VERSION 5.8 ;
BUSBITCHARS "[]" ;
DIVIDERCHAR "/" ;
UNITS
    DATABASE MICRONS 1000 ;
END UNITS

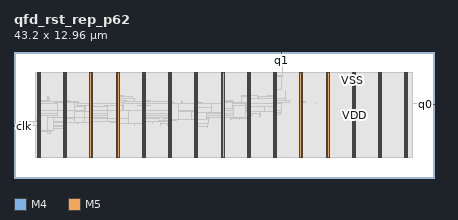
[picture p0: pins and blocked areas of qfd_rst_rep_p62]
MACRO qfd_rst_rep_p62
  FOREIGN qfd_rst_rep_p62 0 0 ;
  CLASS BLOCK ;
  SIZE 43.2 BY 12.96 ;
  PIN clk
    DIRECTION INPUT ;
    USE SIGNAL ;
    PORT
      LAYER M4 ;
        RECT  0 5.328 0.084 5.352 ;
    END
  END clk
  PIN d
    DIRECTION INPUT ;
    USE SIGNAL ;
    PORT
      LAYER M4 ;
        RECT  0 5.424 0.084 5.448 ;
    END
  END d
  PIN q0
    DIRECTION OUTPUT ;
    USE SIGNAL ;
    PORT
      LAYER M4 ;
        RECT  43.116 7.536 43.2 7.56 ;
    END
    PORT
      LAYER M4 ;
        RECT  43.081 7.536 43.164 7.56 ;
    END
  END q0
  PIN q1
    DIRECTION OUTPUT ;
    USE SIGNAL ;
    PORT
      LAYER M5 ;
        RECT  27.504 12.876 27.528 12.96 ;
    END
    PORT
      LAYER M5 ;
        RECT  27.504 12.805 27.528 12.944 ;
    END
  END q1
  PIN VSS
    DIRECTION INOUT ;
    USE GROUND ;
    PORT
      LAYER M5 ;
        RECT  40.2 2.137 40.32 10.823 ;
        RECT  37.5 2.137 37.62 10.823 ;
        RECT  34.8 2.137 34.92 10.823 ;
        RECT  32.1 2.137 32.22 10.823 ;
        RECT  29.4 2.137 29.52 10.823 ;
        RECT  26.7 2.137 26.82 10.823 ;
        RECT  24 2.137 24.12 10.823 ;
        RECT  21.3 2.137 21.42 10.823 ;
        RECT  18.6 2.137 18.72 10.823 ;
        RECT  15.9 2.137 16.02 10.823 ;
        RECT  13.2 2.137 13.32 10.823 ;
        RECT  10.5 2.137 10.62 10.823 ;
        RECT  7.8 2.137 7.92 10.823 ;
        RECT  5.1 2.137 5.22 10.823 ;
        RECT  2.4 2.137 2.52 10.823 ;
    END
  END VSS
  PIN VDD
    DIRECTION INOUT ;
    USE POWER ;
    PORT
      LAYER M5 ;
        RECT  40.392 2.151 40.512 10.809 ;
        RECT  37.692 2.151 37.812 10.809 ;
        RECT  34.992 2.151 35.112 10.809 ;
        RECT  32.292 2.151 32.412 10.809 ;
        RECT  29.592 2.151 29.712 10.809 ;
        RECT  26.892 2.151 27.012 10.809 ;
        RECT  24.192 2.151 24.312 10.809 ;
        RECT  21.492 2.151 21.612 10.809 ;
        RECT  18.792 2.151 18.912 10.809 ;
        RECT  16.092 2.151 16.212 10.809 ;
        RECT  13.392 2.151 13.512 10.809 ;
        RECT  10.692 2.151 10.812 10.809 ;
        RECT  7.992 2.151 8.112 10.809 ;
        RECT  5.292 2.151 5.412 10.809 ;
        RECT  2.592 2.151 2.712 10.809 ;
    END
  END VDD
  # OT_OBS_CLOSED layer=M5 d_um=1.536 added=7
  OBS
    LAYER RVTN ;
     RECT  2.16 2.16 41.04 2.295 ;
     RECT  2.16 2.565 41.04 2.835 ;
     RECT  2.16 3.105 41.04 3.375 ;
     RECT  2.16 3.645 41.04 3.915 ;
     RECT  2.16 4.185 41.04 4.455 ;
     RECT  2.16 4.725 41.04 4.995 ;
     RECT  2.16 5.265 41.04 5.535 ;
     RECT  2.16 5.805 41.04 6.075 ;
     RECT  2.16 6.345 41.04 6.615 ;
     RECT  2.16 6.885 41.04 7.155 ;
     RECT  2.16 7.425 41.04 7.695 ;
     RECT  2.16 7.965 41.04 8.235 ;
     RECT  2.16 8.505 41.04 8.775 ;
     RECT  2.16 9.045 41.04 9.315 ;
     RECT  2.16 9.585 41.04 9.855 ;
     RECT  2.16 10.125 41.04 10.395 ;
     RECT  2.16 10.665 41.04 10.8 ;
    LAYER RVTP ;
     RECT  2.16 2.295 41.04 2.565 ;
     RECT  2.16 2.835 41.04 3.105 ;
     RECT  2.16 3.375 41.04 3.645 ;
     RECT  2.16 3.915 41.04 4.185 ;
     RECT  2.16 4.455 41.04 4.725 ;
     RECT  2.16 4.995 41.04 5.265 ;
     RECT  2.16 5.535 41.04 5.805 ;
     RECT  2.16 6.075 41.04 6.345 ;
     RECT  2.16 6.615 41.04 6.885 ;
     RECT  2.16 7.155 41.04 7.425 ;
     RECT  2.16 7.695 41.04 7.965 ;
     RECT  2.16 8.235 41.04 8.505 ;
     RECT  2.16 8.775 41.04 9.045 ;
     RECT  2.16 9.315 41.04 9.585 ;
     RECT  2.16 9.855 41.04 10.125 ;
     RECT  2.16 10.395 41.04 10.665 ;
    LAYER M1 ;
     RECT  2.16 2.151 41.04 10.809 ;
    LAYER M2 ;
     RECT  2.16 2.151 41.04 10.809 ;
     RECT  41.04 7.632 43.115 7.65 ;
    LAYER M3 ;
     RECT  2.415 2.143 2.505 2.413 ;
     RECT  5.115 2.143 5.205 2.413 ;
     RECT  7.815 2.143 7.905 2.413 ;
     RECT  10.515 2.143 10.605 2.413 ;
     RECT  13.215 2.143 13.305 2.413 ;
     RECT  15.915 2.143 16.005 2.413 ;
     RECT  18.615 2.143 18.705 2.413 ;
     RECT  21.315 2.143 21.405 2.413 ;
     RECT  24.015 2.143 24.105 2.413 ;
     RECT  26.715 2.143 26.805 2.413 ;
     RECT  29.415 2.143 29.505 2.413 ;
     RECT  32.115 2.143 32.205 2.413 ;
     RECT  34.815 2.143 34.905 2.413 ;
     RECT  37.515 2.143 37.605 2.413 ;
     RECT  40.215 2.143 40.305 2.413 ;
     RECT  2.415 2.413 2.697 4.531 ;
     RECT  2.415 4.531 2.754 4.765 ;
     RECT  3.492 4.531 3.762 4.765 ;
     RECT  2.415 4.765 3.762 4.801 ;
     RECT  2.415 4.801 3.87 4.891 ;
     RECT  2.415 4.891 4.086 5.071 ;
     RECT  5.115 2.413 5.397 5.071 ;
     RECT  2.415 5.071 5.397 5.305 ;
     RECT  18.615 2.413 18.897 5.341 ;
     RECT  19.872 5.197 19.89 5.341 ;
     RECT  2.376 5.305 5.397 5.419 ;
     RECT  15.915 2.413 16.197 5.431 ;
     RECT  12.42 5.431 12.438 5.575 ;
     RECT  6.408 5.575 6.426 5.611 ;
     RECT  11.736 5.575 12.438 5.611 ;
     RECT  13.215 2.413 13.497 5.611 ;
     RECT  15.048 5.431 15.066 5.611 ;
     RECT  15.804 5.431 16.197 5.611 ;
     RECT  18.615 5.341 19.89 5.611 ;
     RECT  10.515 2.413 10.797 5.701 ;
     RECT  2.304 5.419 5.397 5.707 ;
     RECT  6.408 5.611 6.642 5.707 ;
     RECT  14.22 5.611 14.238 5.8 ;
     RECT  15.048 5.611 16.197 5.8 ;
     RECT  7.815 2.413 8.097 5.809 ;
     RECT  9.972 5.701 10.797 5.845 ;
     RECT  11.736 5.611 13.497 5.845 ;
     RECT  2.304 5.707 5.49 5.881 ;
     RECT  6.408 5.707 6.858 5.881 ;
     RECT  14.22 5.8 16.197 5.881 ;
     RECT  7.632 5.809 8.097 5.971 ;
     RECT  2.304 5.881 6.858 6.035 ;
     RECT  2.412 6.035 6.858 6.043 ;
     RECT  7.632 5.971 8.514 6.043 ;
     RECT  9.756 5.845 13.497 6.043 ;
     RECT  14.22 5.881 16.686 6.043 ;
     RECT  2.412 6.043 8.514 6.115 ;
     RECT  9.756 6.043 16.686 6.115 ;
     RECT  18.615 5.611 19.962 6.115 ;
     RECT  22.32 5.971 22.338 6.115 ;
     RECT  23.148 6.043 23.166 6.115 ;
     RECT  2.412 6.115 16.686 6.151 ;
     RECT  17.712 6.115 19.962 6.151 ;
     RECT  22.32 6.115 23.166 6.151 ;
     RECT  24.015 2.413 24.297 6.151 ;
     RECT  2.412 6.151 20.142 6.241 ;
     RECT  21.315 2.413 21.597 6.241 ;
     RECT  22.32 6.151 24.297 6.241 ;
     RECT  2.412 6.241 24.297 6.385 ;
     RECT  2.412 6.385 24.534 6.413 ;
     RECT  25.272 6.241 25.29 6.421 ;
     RECT  26.715 2.413 26.997 6.511 ;
     RECT  2.415 6.413 24.534 6.655 ;
     RECT  25.272 6.421 25.362 6.655 ;
     RECT  26.715 6.511 27.45 6.691 ;
     RECT  2.415 6.655 25.362 6.961 ;
     RECT  26.715 6.691 27.558 6.961 ;
     RECT  2.415 6.961 27.558 7.619 ;
     RECT  7.815 7.619 8.19 7.655 ;
     RECT  9.324 7.619 9.342 7.655 ;
     RECT  18.615 7.619 20.034 7.655 ;
     RECT  21.315 7.619 24.354 7.655 ;
     RECT  25.092 7.619 27.558 7.655 ;
     RECT  43.092 7.531 43.11 7.655 ;
     RECT  10.515 7.619 17.334 7.664 ;
     RECT  18.615 7.655 19.458 7.691 ;
     RECT  18.615 7.691 19.422 7.727 ;
     RECT  21.315 7.655 24.297 7.763 ;
     RECT  25.128 7.655 27.558 7.771 ;
     RECT  29.415 2.413 29.697 7.771 ;
     RECT  30.996 7.627 31.014 7.799 ;
     RECT  2.415 7.619 6.678 7.889 ;
     RECT  10.515 7.664 16.398 7.889 ;
     RECT  17.208 7.664 17.334 7.889 ;
     RECT  18.615 7.727 18.954 7.889 ;
     RECT  21.315 7.763 22.626 7.889 ;
     RECT  29.415 7.771 29.97 7.889 ;
     RECT  2.415 7.889 4.158 7.901 ;
     RECT  2.415 7.901 3.69 7.925 ;
     RECT  5.115 7.889 5.706 7.925 ;
     RECT  13.215 7.889 14.022 7.925 ;
     RECT  17.208 7.889 17.226 7.925 ;
     RECT  21.315 7.889 22.446 7.925 ;
     RECT  25.128 7.771 28.314 7.925 ;
     RECT  3.492 7.925 3.69 8.195 ;
     RECT  10.515 7.889 12.438 8.195 ;
     RECT  25.128 7.925 27.954 8.195 ;
     RECT  3.492 8.195 3.51 8.339 ;
     RECT  23.364 7.763 24.297 8.395 ;
     RECT  25.128 8.195 26.997 8.395 ;
     RECT  10.515 8.195 12.222 8.429 ;
     RECT  23.364 8.395 26.997 8.429 ;
     RECT  10.515 8.429 11.286 8.465 ;
     RECT  23.364 8.429 25.002 8.465 ;
     RECT  26.028 8.429 26.997 8.501 ;
     RECT  27.936 8.195 27.954 9.041 ;
     RECT  26.715 8.501 26.997 9.121 ;
     RECT  26.715 9.121 27.486 10.471 ;
     RECT  2.415 7.925 2.697 10.547 ;
     RECT  5.115 7.925 5.397 10.547 ;
     RECT  7.815 7.655 8.097 10.547 ;
     RECT  10.515 8.465 10.797 10.547 ;
     RECT  13.215 7.925 13.497 10.547 ;
     RECT  15.915 7.889 16.197 10.547 ;
     RECT  18.615 7.889 18.897 10.547 ;
     RECT  21.315 7.925 21.597 10.547 ;
     RECT  24.015 8.465 24.297 10.547 ;
     RECT  26.715 10.471 27.666 10.547 ;
     RECT  29.415 7.889 29.697 10.547 ;
     RECT  32.115 2.413 32.397 10.547 ;
     RECT  34.815 2.413 35.097 10.547 ;
     RECT  37.515 2.413 37.797 10.547 ;
     RECT  40.215 2.413 40.497 10.547 ;
     RECT  2.415 10.547 2.505 10.817 ;
     RECT  5.115 10.547 5.205 10.817 ;
     RECT  7.815 10.547 7.905 10.817 ;
     RECT  10.515 10.547 10.605 10.817 ;
     RECT  13.215 10.547 13.305 10.817 ;
     RECT  15.915 10.547 16.005 10.817 ;
     RECT  18.615 10.547 18.705 10.817 ;
     RECT  21.315 10.547 21.405 10.817 ;
     RECT  24.015 10.547 24.105 10.817 ;
     RECT  26.715 10.547 26.805 10.817 ;
     RECT  29.415 10.547 29.505 10.817 ;
     RECT  32.115 10.547 32.205 10.817 ;
     RECT  34.815 10.547 34.905 10.817 ;
     RECT  37.515 10.547 37.605 10.817 ;
     RECT  40.215 10.547 40.305 10.817 ;
     RECT  27.648 10.547 27.666 12.845 ;
    LAYER M4 ;
     RECT  0.084 5.328 0.517 5.352 ;
     RECT  0.06 5.352 0.517 5.424 ;
     RECT  0.084 5.424 0.517 5.448 ;
     RECT  0.517 5.328 0.563 5.832 ;
     RECT  0.563 5.424 2.401 5.832 ;
     RECT  2.401 5.424 2.408 6.408 ;
     RECT  2.408 2.148 2.512 10.812 ;
     RECT  2.512 2.418 2.704 10.542 ;
     RECT  2.704 4.896 3.443 6.408 ;
     RECT  3.443 4.896 4.097 6.264 ;
     RECT  2.704 7.872 4.129 7.896 ;
     RECT  4.097 5.808 5.108 6.264 ;
     RECT  4.129 7.728 5.108 7.896 ;
     RECT  5.108 2.148 5.212 10.812 ;
     RECT  5.212 2.418 5.404 10.542 ;
     RECT  5.404 5.712 6.265 7.752 ;
     RECT  6.265 7.344 6.545 7.752 ;
     RECT  6.265 5.712 7.237 6.216 ;
     RECT  6.545 7.344 7.237 7.464 ;
     RECT  7.237 5.712 7.808 7.464 ;
     RECT  7.808 2.148 7.912 10.812 ;
     RECT  7.912 2.418 8.104 10.542 ;
     RECT  8.104 7.344 8.201 7.464 ;
     RECT  8.201 7.344 9.313 7.368 ;
     RECT  8.104 5.808 9.637 6.072 ;
     RECT  9.637 5.808 10.508 6.168 ;
     RECT  9.313 7.344 10.508 7.464 ;
     RECT  10.508 2.148 10.612 10.812 ;
     RECT  10.612 2.418 10.804 10.542 ;
     RECT  10.804 5.616 11.26 7.992 ;
     RECT  11.26 7.968 11.549 7.992 ;
     RECT  11.26 5.616 11.747 6.888 ;
     RECT  11.747 5.616 11.788 6.264 ;
     RECT  11.788 5.808 13.208 6.264 ;
     RECT  12.697 7.44 13.208 7.464 ;
     RECT  13.208 2.148 13.312 10.812 ;
     RECT  13.312 2.418 13.504 10.542 ;
     RECT  13.504 7.44 14.033 7.464 ;
     RECT  13.504 5.808 14.893 6.12 ;
     RECT  14.893 5.808 14.897 6.264 ;
     RECT  14.897 5.904 15.908 6.264 ;
     RECT  14.929 7.632 15.908 7.656 ;
     RECT  15.908 2.148 16.012 10.812 ;
     RECT  16.012 2.418 16.204 10.542 ;
     RECT  16.204 6.048 16.949 7.656 ;
     RECT  16.949 6.048 18.277 6.84 ;
     RECT  18.277 6.048 18.608 6.888 ;
     RECT  18.608 2.148 18.712 10.812 ;
     RECT  18.712 2.418 18.904 10.542 ;
     RECT  18.904 6.048 19.289 7.224 ;
     RECT  19.289 6.048 19.829 6.072 ;
     RECT  19.289 7.2 20.005 7.224 ;
     RECT  20.005 7.2 20.252 7.608 ;
     RECT  20.252 6.72 20.339 7.608 ;
     RECT  20.339 7.2 21.308 7.416 ;
     RECT  21.308 2.148 21.412 10.812 ;
     RECT  21.412 2.418 21.604 10.542 ;
     RECT  21.604 7.2 22.457 7.752 ;
     RECT  22.457 7.2 22.597 7.416 ;
     RECT  22.597 6.24 23.852 7.416 ;
     RECT  23.852 6.24 24.008 7.608 ;
     RECT  24.008 2.148 24.112 10.812 ;
     RECT  24.112 2.418 24.304 10.542 ;
     RECT  24.304 6.816 25.043 8.424 ;
     RECT  25.043 6.816 26.708 8.184 ;
     RECT  26.708 2.148 26.812 10.812 ;
     RECT  26.812 2.418 27.004 10.542 ;
     RECT  27.004 7.728 27.389 7.752 ;
     RECT  27.493 12.816 27.677 12.84 ;
     RECT  29.408 2.148 29.512 10.812 ;
     RECT  29.512 2.418 29.704 10.542 ;
     RECT  32.108 2.148 32.212 10.812 ;
     RECT  32.212 2.418 32.404 10.542 ;
     RECT  34.808 2.148 34.912 10.812 ;
     RECT  34.912 2.418 35.104 10.542 ;
     RECT  37.508 2.148 37.612 10.812 ;
     RECT  37.612 2.418 37.804 10.542 ;
     RECT  40.208 2.148 40.312 10.812 ;
     RECT  40.312 2.418 40.504 10.542 ;
    LAYER M5 ;
     RECT  2.4 2.137 2.52 2.151 ;
     RECT  5.1 2.137 5.22 2.151 ;
     RECT  7.8 2.137 7.92 2.151 ;
     RECT  10.5 2.137 10.62 2.151 ;
     RECT  13.2 2.137 13.32 2.151 ;
     RECT  15.9 2.137 16.02 2.151 ;
     RECT  18.6 2.137 18.72 2.151 ;
     RECT  21.3 2.137 21.42 2.151 ;
     RECT  24 2.137 24.12 2.151 ;
     RECT  26.7 2.137 26.82 2.151 ;
     RECT  29.4 2.137 29.52 2.151 ;
     RECT  32.1 2.137 32.22 2.151 ;
     RECT  34.8 2.137 34.92 2.151 ;
     RECT  37.5 2.137 37.62 2.151 ;
     RECT  40.2 2.137 40.32 2.151 ;
     RECT  2.4 2.151 2.712 4.885 ;
     RECT  10.5 2.151 10.812 5.605 ;
     RECT  0.528 5.317 0.552 5.843 ;
     RECT  15.9 2.151 16.212 5.893 ;
     RECT  18.6 2.151 18.912 6.037 ;
     RECT  15.408 5.893 16.212 6.083 ;
     RECT  5.1 2.151 5.412 6.133 ;
     RECT  10.5 5.605 11.736 6.133 ;
     RECT  5.1 6.133 6.216 6.181 ;
     RECT  7.8 2.151 8.112 6.181 ;
     RECT  2.4 4.885 3.432 6.419 ;
     RECT  18.6 6.037 19.752 6.709 ;
     RECT  24 2.151 24.312 6.805 ;
     RECT  26.7 2.151 27.012 6.805 ;
     RECT  7.248 6.181 8.112 6.851 ;
     RECT  4.512 6.181 6.216 6.899 ;
     RECT  9.648 6.133 11.736 6.899 ;
     RECT  18.6 6.709 20.328 7.235 ;
     RECT  23.904 6.805 24.312 7.381 ;
     RECT  25.776 6.805 27.012 7.381 ;
     RECT  7.344 6.851 8.112 7.475 ;
     RECT  9.648 6.899 11.208 7.475 ;
     RECT  20.304 7.235 20.328 7.619 ;
     RECT  23.904 7.381 27.012 7.619 ;
     RECT  10.5 7.475 11.208 7.715 ;
     RECT  4.512 6.899 5.412 7.763 ;
     RECT  24 7.619 27.012 8.195 ;
     RECT  24 8.195 25.032 8.435 ;
     RECT  2.4 6.419 2.712 10.809 ;
     RECT  5.1 7.763 5.412 10.809 ;
     RECT  7.8 7.475 8.112 10.809 ;
     RECT  10.5 7.715 10.812 10.809 ;
     RECT  13.2 2.151 13.512 10.809 ;
     RECT  15.9 6.083 16.212 10.809 ;
     RECT  18.6 7.235 18.912 10.809 ;
     RECT  21.3 2.151 21.612 10.809 ;
     RECT  24 8.435 24.312 10.809 ;
     RECT  26.7 8.195 27.012 10.809 ;
     RECT  29.4 2.151 29.712 10.809 ;
     RECT  32.1 2.151 32.412 10.809 ;
     RECT  34.8 2.151 35.112 10.809 ;
     RECT  37.5 2.151 37.812 10.809 ;
     RECT  40.2 2.151 40.512 10.809 ;
     RECT  2.4 10.809 2.52 10.823 ;
     RECT  5.1 10.809 5.22 10.823 ;
     RECT  7.8 10.809 7.92 10.823 ;
     RECT  10.5 10.809 10.62 10.823 ;
     RECT  13.2 10.809 13.32 10.823 ;
     RECT  15.9 10.809 16.02 10.823 ;
     RECT  18.6 10.809 18.72 10.823 ;
     RECT  21.3 10.809 21.42 10.823 ;
     RECT  24 10.809 24.12 10.823 ;
     RECT  26.7 10.809 26.82 10.823 ;
     RECT  29.4 10.809 29.52 10.823 ;
     RECT  32.1 10.809 32.22 10.823 ;
     RECT  34.8 10.809 34.92 10.823 ;
     RECT  37.5 10.809 37.62 10.823 ;
     RECT  40.2 10.809 40.32 10.823 ;
     RECT  11.736 5.605 13.2 6.899 ;
     RECT  3.432 6.181 4.512 6.419 ;
     RECT  6.216 6.181 7.248 6.851 ;
     RECT  20.328 6.709 21.3 7.619 ;
     RECT  24.312 6.805 25.776 7.381 ;
     RECT  6.216 6.851 7.344 6.899 ;
     RECT  18.912 7.235 20.304 7.619 ;
  END
END qfd_rst_rep_p62
END LIBRARY
